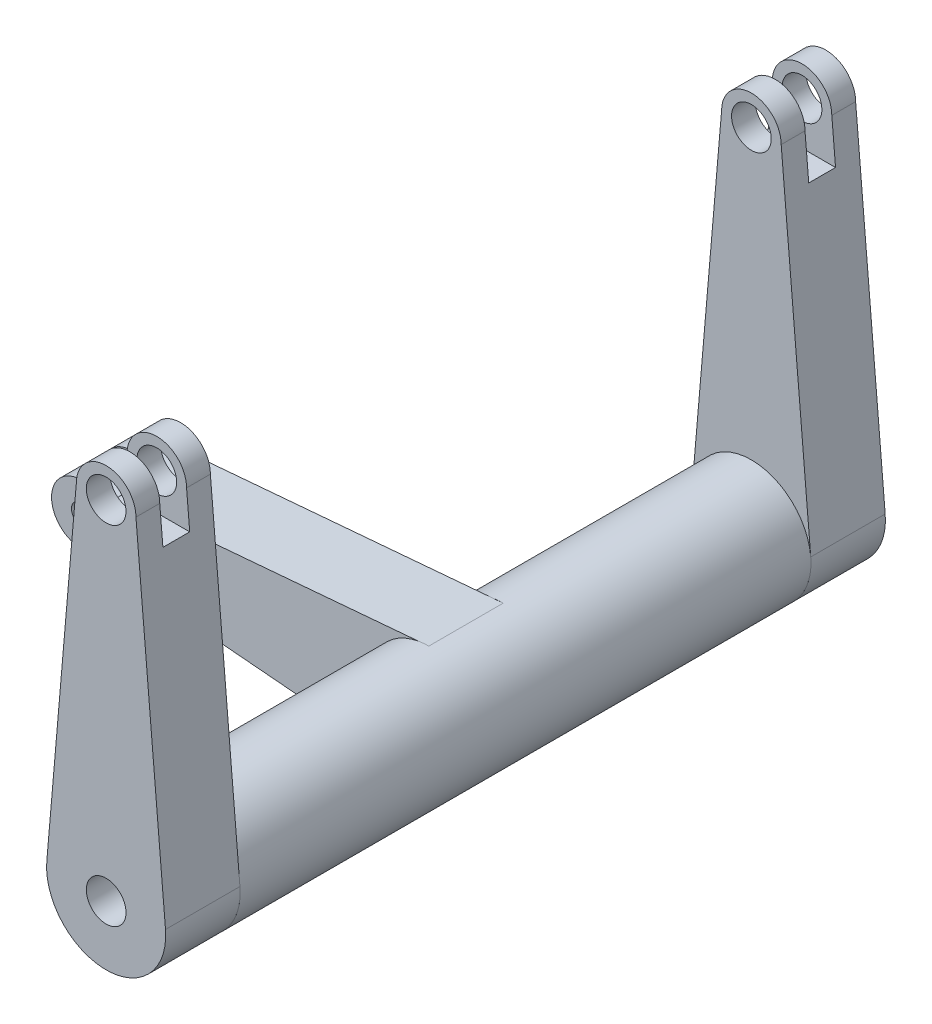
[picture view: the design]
ISO-10303-21;
HEADER;
FILE_DESCRIPTION(('STEP AP214'),'2;1');
FILE_NAME('part.step','',(''),(''),'','','');
FILE_SCHEMA(('AUTOMOTIVE_DESIGN { 1 0 10303 214 1 1 1 1 }'));
ENDSEC;
DATA;
#1=APPLICATION_CONTEXT('core data for automotive mechanical design processes');
#2=APPLICATION_PROTOCOL_DEFINITION('international standard','automotive_design',2000,#1);
#3=PRODUCT_CONTEXT('',#1,'mechanical');
#4=PRODUCT('Part','Part','',(#3));
#5=PRODUCT_RELATED_PRODUCT_CATEGORY('part','',(#4));
#6=PRODUCT_DEFINITION_FORMATION('','',#4);
#7=PRODUCT_DEFINITION_CONTEXT('part definition',#1,'design');
#8=PRODUCT_DEFINITION('design','',#6,#7);
#9=PRODUCT_DEFINITION_SHAPE('','',#8);
#10=(LENGTH_UNIT() NAMED_UNIT(*) SI_UNIT(.MILLI.,.METRE.));
#11=(NAMED_UNIT(*) PLANE_ANGLE_UNIT() SI_UNIT($,.RADIAN.));
#12=(NAMED_UNIT(*) SI_UNIT($,.STERADIAN.) SOLID_ANGLE_UNIT());
#13=UNCERTAINTY_MEASURE_WITH_UNIT(LENGTH_MEASURE(1.E-05),#10,'distance_accuracy_value','');
#14=(GEOMETRIC_REPRESENTATION_CONTEXT(3) GLOBAL_UNCERTAINTY_ASSIGNED_CONTEXT((#13)) GLOBAL_UNIT_ASSIGNED_CONTEXT((#10,
#11,#12)) REPRESENTATION_CONTEXT('',''));
#15=CARTESIAN_POINT('',(0.,0.,0.));
#16=DIRECTION('',(0.,0.,1.));
#17=DIRECTION('',(1.,0.,0.));
#18=AXIS2_PLACEMENT_3D('',#15,#16,#17);
#19=CARTESIAN_POINT('',(88.9,-82.0397739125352,-92.075));
#20=DIRECTION('',(0.,0.,1.));
#21=DIRECTION('',(1.,0.,0.));
#22=AXIS2_PLACEMENT_3D('',#19,#20,#21);
#23=CYLINDRICAL_SURFACE('',#22,7.62);
#24=CARTESIAN_POINT('',(88.9,-82.0397739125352,-79.121));
#25=DIRECTION('',(0.,0.,-1.));
#26=DIRECTION('',(0.,1.,0.));
#27=AXIS2_PLACEMENT_3D('',#24,#25,#26);
#28=CIRCLE('',#27,7.62);
#29=CARTESIAN_POINT('',(81.28,-82.0397739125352,-79.121));
#30=VERTEX_POINT('',#29);
#31=CARTESIAN_POINT('',(96.52,-82.0397739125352,-79.121));
#32=VERTEX_POINT('',#31);
#33=EDGE_CURVE('E245',#30,#32,#28,.T.);
#34=ORIENTED_EDGE('',*,*,#33,.F.);
#35=DIRECTION('',(0.,0.,1.));
#36=VECTOR('',#35,1.);
#37=CARTESIAN_POINT('',(81.28,-82.0397739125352,-92.075));
#38=LINE('',#37,#36);
#39=CARTESIAN_POINT('',(81.28,-82.0397739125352,-73.025));
#40=VERTEX_POINT('',#39);
#41=EDGE_CURVE('E297',#30,#40,#38,.T.);
#42=ORIENTED_EDGE('',*,*,#41,.T.);
#43=CARTESIAN_POINT('',(88.9,-82.0397739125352,-73.025));
#44=DIRECTION('',(0.,0.,-1.));
#45=DIRECTION('',(-1.,0.,0.));
#46=AXIS2_PLACEMENT_3D('',#43,#44,#45);
#47=CIRCLE('',#46,7.62);
#48=CARTESIAN_POINT('',(96.52,-82.0397739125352,-73.025));
#49=VERTEX_POINT('',#48);
#50=EDGE_CURVE('E286',#40,#49,#47,.T.);
#51=ORIENTED_EDGE('',*,*,#50,.T.);
#52=DIRECTION('',(0.,0.,1.));
#53=VECTOR('',#52,1.);
#54=CARTESIAN_POINT('',(96.52,-82.0397739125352,-92.075));
#55=LINE('',#54,#53);
#56=EDGE_CURVE('E319',#32,#49,#55,.T.);
#57=ORIENTED_EDGE('',*,*,#56,.F.);
#58=EDGE_LOOP('',(#34,#42,#51,#57));
#59=FACE_BOUND('',#58,.T.);
#60=ADVANCED_FACE('F32',(#59),#23,.T.);
#61=CARTESIAN_POINT('',(88.9,-82.0397739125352,-85.979));
#62=DIRECTION('',(0.,0.,1.));
#63=DIRECTION('',(0.,-1.,0.));
#64=AXIS2_PLACEMENT_3D('',#61,#62,#63);
#65=CIRCLE('',#64,7.62);
#66=CARTESIAN_POINT('',(96.52,-82.0397739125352,-85.979));
#67=VERTEX_POINT('',#66);
#68=CARTESIAN_POINT('',(81.28,-82.0397739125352,-85.979));
#69=VERTEX_POINT('',#68);
#70=EDGE_CURVE('E47',#67,#69,#65,.T.);
#71=ORIENTED_EDGE('',*,*,#70,.F.);
#72=CARTESIAN_POINT('',(96.52,-82.0397739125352,-92.075));
#73=VERTEX_POINT('',#72);
#74=EDGE_CURVE('E236',#73,#67,#55,.T.);
#75=ORIENTED_EDGE('',*,*,#74,.F.);
#76=CARTESIAN_POINT('',(88.9,-82.0397739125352,-92.075));
#77=DIRECTION('',(0.,0.,-1.));
#78=DIRECTION('',(-1.,0.,0.));
#79=AXIS2_PLACEMENT_3D('',#76,#77,#78);
#80=CIRCLE('',#79,7.62);
#81=CARTESIAN_POINT('',(81.28,-82.0397739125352,-92.075));
#82=VERTEX_POINT('',#81);
#83=EDGE_CURVE('E287',#82,#73,#80,.T.);
#84=ORIENTED_EDGE('',*,*,#83,.F.);
#85=EDGE_CURVE('E310',#82,#69,#38,.T.);
#86=ORIENTED_EDGE('',*,*,#85,.T.);
#87=EDGE_LOOP('',(#71,#75,#84,#86));
#88=FACE_BOUND('',#87,.T.);
#89=ADVANCED_FACE('F595',(#88),#23,.T.);
#90=CARTESIAN_POINT('',(96.52,-82.0397739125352,-92.075));
#91=DIRECTION('',(-0.996292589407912,-0.0860295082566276,0.));
#92=DIRECTION('',(0.0860295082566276,-0.996292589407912,0.));
#93=AXIS2_PLACEMENT_3D('',#90,#91,#92);
#94=PLANE('',#93);
#95=DIRECTION('',(0.0860295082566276,-0.996292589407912,0.));
#96=VECTOR('',#95,1.);
#97=CARTESIAN_POINT('',(96.52,-82.0397739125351,-79.121));
#98=LINE('',#97,#96);
#99=CARTESIAN_POINT('',(97.4756411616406,-93.106885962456,-79.121));
#100=VERTEX_POINT('',#99);
#101=EDGE_CURVE('E227',#32,#100,#98,.T.);
#102=ORIENTED_EDGE('',*,*,#101,.F.);
#103=ORIENTED_EDGE('',*,*,#56,.T.);
#104=DIRECTION('',(0.0860295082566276,-0.996292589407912,0.));
#105=VECTOR('',#104,1.);
#106=CARTESIAN_POINT('',(96.52,-82.0397739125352,-73.025));
#107=LINE('',#106,#105);
#108=CARTESIAN_POINT('',(104.076113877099,-169.545798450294,-73.025));
#109=VERTEX_POINT('',#108);
#110=EDGE_CURVE('E300',#49,#109,#107,.T.);
#111=ORIENTED_EDGE('',*,*,#110,.T.);
#112=CARTESIAN_POINT('',(104.083272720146,-169.628703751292,-73.025));
#113=VERTEX_POINT('',#112);
#114=EDGE_CURVE('E304',#109,#113,#107,.T.);
#115=ORIENTED_EDGE('',*,*,#114,.T.);
#116=DIRECTION('',(0.,0.,1.));
#117=VECTOR('',#116,1.);
#118=CARTESIAN_POINT('',(104.083272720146,-169.628703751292,-92.075));
#119=LINE('',#118,#117);
#120=CARTESIAN_POINT('',(104.083272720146,-169.628703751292,-92.075));
#121=VERTEX_POINT('',#120);
#122=EDGE_CURVE('E316',#121,#113,#119,.T.);
#123=ORIENTED_EDGE('',*,*,#122,.F.);
#124=DIRECTION('',(0.0860295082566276,-0.996292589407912,0.));
#125=VECTOR('',#124,1.);
#126=CARTESIAN_POINT('',(96.52,-82.0397739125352,-92.075));
#127=LINE('',#126,#125);
#128=EDGE_CURVE('E290',#73,#121,#127,.T.);
#129=ORIENTED_EDGE('',*,*,#128,.F.);
#130=ORIENTED_EDGE('',*,*,#74,.T.);
#131=DIRECTION('',(-0.0860295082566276,0.996292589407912,0.));
#132=VECTOR('',#131,1.);
#133=CARTESIAN_POINT('',(96.52,-82.0397739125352,-85.979));
#134=LINE('',#133,#132);
#135=CARTESIAN_POINT('',(97.4756411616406,-93.106885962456,-85.979));
#136=VERTEX_POINT('',#135);
#137=EDGE_CURVE('E230',#136,#67,#134,.T.);
#138=ORIENTED_EDGE('',*,*,#137,.F.);
#139=DIRECTION('',(0.,0.,-1.));
#140=VECTOR('',#139,1.);
#141=CARTESIAN_POINT('',(97.4756411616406,-93.106885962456,-92.075));
#142=LINE('',#141,#140);
#143=EDGE_CURVE('E217',#100,#136,#142,.T.);
#144=ORIENTED_EDGE('',*,*,#143,.F.);
#145=EDGE_LOOP('',(#102,#103,#111,#115,#123,#129,#130,#138,#144));
#146=FACE_BOUND('',#145,.T.);
#147=ADVANCED_FACE('F234',(#146),#94,.F.);
#148=CARTESIAN_POINT('',(73.716727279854,-169.628703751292,-92.075));
#149=DIRECTION('',(0.996292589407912,-0.0860295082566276,0.));
#150=DIRECTION('',(0.0860295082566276,0.996292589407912,0.));
#151=AXIS2_PLACEMENT_3D('',#148,#149,#150);
#152=PLANE('',#151);
#153=DIRECTION('',(0.0860295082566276,0.996292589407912,0.));
#154=VECTOR('',#153,1.);
#155=CARTESIAN_POINT('',(73.716727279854,-169.628703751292,-79.1209999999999));
#156=LINE('',#155,#154);
#157=CARTESIAN_POINT('',(80.3243588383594,-93.106885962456,-79.121));
#158=VERTEX_POINT('',#157);
#159=EDGE_CURVE('E240',#158,#30,#156,.T.);
#160=ORIENTED_EDGE('',*,*,#159,.F.);
#161=DIRECTION('',(0.,0.,1.));
#162=VECTOR('',#161,1.);
#163=CARTESIAN_POINT('',(80.3243588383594,-93.106885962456,-92.075));
#164=LINE('',#163,#162);
#165=CARTESIAN_POINT('',(80.3243588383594,-93.106885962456,-85.979));
#166=VERTEX_POINT('',#165);
#167=EDGE_CURVE('E11',#166,#158,#164,.T.);
#168=ORIENTED_EDGE('',*,*,#167,.F.);
#169=DIRECTION('',(-0.0860295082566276,-0.996292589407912,0.));
#170=VECTOR('',#169,1.);
#171=CARTESIAN_POINT('',(73.716727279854,-169.628703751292,-85.9790000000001));
#172=LINE('',#171,#170);
#173=EDGE_CURVE('E231',#69,#166,#172,.T.);
#174=ORIENTED_EDGE('',*,*,#173,.F.);
#175=ORIENTED_EDGE('',*,*,#85,.F.);
#176=DIRECTION('',(0.0860295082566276,0.996292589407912,0.));
#177=VECTOR('',#176,1.);
#178=CARTESIAN_POINT('',(73.716727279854,-169.628703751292,-92.075));
#179=LINE('',#178,#177);
#180=CARTESIAN_POINT('',(73.716727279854,-169.628703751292,-92.075));
#181=VERTEX_POINT('',#180);
#182=EDGE_CURVE('E295',#181,#82,#179,.T.);
#183=ORIENTED_EDGE('',*,*,#182,.F.);
#184=DIRECTION('',(0.,0.,1.));
#185=VECTOR('',#184,1.);
#186=CARTESIAN_POINT('',(73.716727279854,-169.628703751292,-92.075));
#187=LINE('',#186,#185);
#188=CARTESIAN_POINT('',(73.716727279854,-169.628703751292,-73.025));
#189=VERTEX_POINT('',#188);
#190=EDGE_CURVE('E313',#181,#189,#187,.T.);
#191=ORIENTED_EDGE('',*,*,#190,.T.);
#192=DIRECTION('',(0.0860295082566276,0.996292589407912,0.));
#193=VECTOR('',#192,1.);
#194=CARTESIAN_POINT('',(73.716727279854,-169.628703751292,-73.025));
#195=LINE('',#194,#193);
#196=CARTESIAN_POINT('',(73.7238861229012,-169.545798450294,-73.025));
#197=VERTEX_POINT('',#196);
#198=EDGE_CURVE('E291',#189,#197,#195,.T.);
#199=ORIENTED_EDGE('',*,*,#198,.T.);
#200=EDGE_CURVE('E307',#197,#40,#195,.T.);
#201=ORIENTED_EDGE('',*,*,#200,.T.);
#202=ORIENTED_EDGE('',*,*,#41,.F.);
#203=EDGE_LOOP('',(#160,#168,#174,#175,#183,#191,#199,#201,#202));
#204=FACE_BOUND('',#203,.T.);
#205=ADVANCED_FACE('F570',(#204),#152,.F.);
#206=CARTESIAN_POINT('',(88.9,-82.0397739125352,92.075));
#207=DIRECTION('',(0.,0.,-1.));
#208=DIRECTION('',(-1.,0.,0.));
#209=AXIS2_PLACEMENT_3D('',#206,#207,#208);
#210=CYLINDRICAL_SURFACE('',#209,5.08000000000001);
#211=CARTESIAN_POINT('',(88.9,-82.0397739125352,-73.025));
#212=DIRECTION('',(0.,0.,-1.));
#213=DIRECTION('',(-1.,0.,0.));
#214=AXIS2_PLACEMENT_3D('',#211,#212,#213);
#215=CIRCLE('',#214,5.08000000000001);
#216=CARTESIAN_POINT('',(83.82,-82.0397739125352,-73.025));
#217=VERTEX_POINT('',#216);
#218=EDGE_CURVE('E278',#217,#217,#215,.T.);
#219=ORIENTED_EDGE('',*,*,#218,.F.);
#220=EDGE_LOOP('',(#219));
#221=FACE_BOUND('',#220,.T.);
#222=CARTESIAN_POINT('',(88.9,-82.0397739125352,-79.121));
#223=DIRECTION('',(0.,0.,-1.));
#224=DIRECTION('',(0.,1.,0.));
#225=AXIS2_PLACEMENT_3D('',#222,#223,#224);
#226=CIRCLE('',#225,5.08000000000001);
#227=CARTESIAN_POINT('',(88.9,-76.9597739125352,-79.121));
#228=VERTEX_POINT('',#227);
#229=EDGE_CURVE('E237',#228,#228,#226,.F.);
#230=ORIENTED_EDGE('',*,*,#229,.F.);
#231=EDGE_LOOP('',(#230));
#232=FACE_BOUND('',#231,.T.);
#233=ADVANCED_FACE('F850',(#221,#232),#210,.F.);
#234=CARTESIAN_POINT('',(88.9,-82.0397739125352,-92.075));
#235=DIRECTION('',(0.,0.,-1.));
#236=DIRECTION('',(-1.,0.,0.));
#237=AXIS2_PLACEMENT_3D('',#234,#235,#236);
#238=CIRCLE('',#237,5.08000000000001);
#239=CARTESIAN_POINT('',(83.82,-82.0397739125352,-92.075));
#240=VERTEX_POINT('',#239);
#241=EDGE_CURVE('E272',#240,#240,#238,.T.);
#242=ORIENTED_EDGE('',*,*,#241,.T.);
#243=EDGE_LOOP('',(#242));
#244=FACE_BOUND('',#243,.T.);
#245=CARTESIAN_POINT('',(88.9,-82.0397739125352,-85.979));
#246=DIRECTION('',(0.,0.,1.));
#247=DIRECTION('',(0.,-1.,0.));
#248=AXIS2_PLACEMENT_3D('',#245,#246,#247);
#249=CIRCLE('',#248,5.08000000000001);
#250=CARTESIAN_POINT('',(88.9,-87.1197739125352,-85.979));
#251=VERTEX_POINT('',#250);
#252=EDGE_CURVE('E559',#251,#251,#249,.F.);
#253=ORIENTED_EDGE('',*,*,#252,.F.);
#254=EDGE_LOOP('',(#253));
#255=FACE_BOUND('',#254,.T.);
#256=ADVANCED_FACE('F621',(#244,#255),#210,.F.);
#257=CARTESIAN_POINT('',(88.9,-82.0397739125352,92.075));
#258=DIRECTION('',(0.,0.,-1.));
#259=DIRECTION('',(-1.,0.,0.));
#260=AXIS2_PLACEMENT_3D('',#257,#258,#259);
#261=CYLINDRICAL_SURFACE('',#260,7.62);
#262=CARTESIAN_POINT('',(88.9,-82.0397739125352,85.979));
#263=DIRECTION('',(0.,0.,-1.));
#264=DIRECTION('',(0.,1.,0.));
#265=AXIS2_PLACEMENT_3D('',#262,#263,#264);
#266=CIRCLE('',#265,7.62);
#267=CARTESIAN_POINT('',(81.28,-82.0397739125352,85.979));
#268=VERTEX_POINT('',#267);
#269=CARTESIAN_POINT('',(96.52,-82.0397739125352,85.979));
#270=VERTEX_POINT('',#269);
#271=EDGE_CURVE('E262',#268,#270,#266,.T.);
#272=ORIENTED_EDGE('',*,*,#271,.F.);
#273=DIRECTION('',(0.,0.,-1.));
#274=VECTOR('',#273,1.);
#275=CARTESIAN_POINT('',(81.28,-82.0397739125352,92.075));
#276=LINE('',#275,#274);
#277=CARTESIAN_POINT('',(81.28,-82.0397739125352,92.075));
#278=VERTEX_POINT('',#277);
#279=EDGE_CURVE('E355',#278,#268,#276,.T.);
#280=ORIENTED_EDGE('',*,*,#279,.F.);
#281=CARTESIAN_POINT('',(88.9,-82.0397739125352,92.075));
#282=DIRECTION('',(0.,0.,1.));
#283=DIRECTION('',(1.,0.,0.));
#284=AXIS2_PLACEMENT_3D('',#281,#282,#283);
#285=CIRCLE('',#284,7.62);
#286=CARTESIAN_POINT('',(96.52,-82.0397739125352,92.075));
#287=VERTEX_POINT('',#286);
#288=EDGE_CURVE('E322',#287,#278,#285,.T.);
#289=ORIENTED_EDGE('',*,*,#288,.F.);
#290=DIRECTION('',(0.,0.,-1.));
#291=VECTOR('',#290,1.);
#292=CARTESIAN_POINT('',(96.52,-82.0397739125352,92.075));
#293=LINE('',#292,#291);
#294=EDGE_CURVE('E345',#287,#270,#293,.T.);
#295=ORIENTED_EDGE('',*,*,#294,.T.);
#296=EDGE_LOOP('',(#272,#280,#289,#295));
#297=FACE_BOUND('',#296,.T.);
#298=ADVANCED_FACE('F549',(#297),#261,.T.);
#299=CARTESIAN_POINT('',(88.9,-82.0397739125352,79.121));
#300=DIRECTION('',(0.,0.,1.));
#301=DIRECTION('',(0.,-1.,0.));
#302=AXIS2_PLACEMENT_3D('',#299,#300,#301);
#303=CIRCLE('',#302,7.62);
#304=CARTESIAN_POINT('',(96.52,-82.0397739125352,79.121));
#305=VERTEX_POINT('',#304);
#306=CARTESIAN_POINT('',(81.28,-82.0397739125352,79.121));
#307=VERTEX_POINT('',#306);
#308=EDGE_CURVE('E255',#305,#307,#303,.T.);
#309=ORIENTED_EDGE('',*,*,#308,.F.);
#310=CARTESIAN_POINT('',(96.52,-82.0397739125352,73.025));
#311=VERTEX_POINT('',#310);
#312=EDGE_CURVE('E332',#305,#311,#293,.T.);
#313=ORIENTED_EDGE('',*,*,#312,.T.);
#314=CARTESIAN_POINT('',(88.9,-82.0397739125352,73.025));
#315=DIRECTION('',(0.,0.,1.));
#316=DIRECTION('',(1.,0.,0.));
#317=AXIS2_PLACEMENT_3D('',#314,#315,#316);
#318=CIRCLE('',#317,7.62);
#319=CARTESIAN_POINT('',(81.28,-82.0397739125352,73.025));
#320=VERTEX_POINT('',#319);
#321=EDGE_CURVE('E321',#311,#320,#318,.T.);
#322=ORIENTED_EDGE('',*,*,#321,.T.);
#323=EDGE_CURVE('E354',#307,#320,#276,.T.);
#324=ORIENTED_EDGE('',*,*,#323,.F.);
#325=EDGE_LOOP('',(#309,#313,#322,#324));
#326=FACE_BOUND('',#325,.T.);
#327=ADVANCED_FACE('F530',(#326),#261,.T.);
#328=CARTESIAN_POINT('',(81.28,-82.0397739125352,92.075));
#329=DIRECTION('',(0.996292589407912,-0.0860295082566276,0.));
#330=DIRECTION('',(0.0860295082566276,0.996292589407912,0.));
#331=AXIS2_PLACEMENT_3D('',#328,#329,#330);
#332=PLANE('',#331);
#333=DIRECTION('',(0.0860295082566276,0.996292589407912,0.));
#334=VECTOR('',#333,1.);
#335=CARTESIAN_POINT('',(81.28,-82.0397739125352,85.979));
#336=LINE('',#335,#334);
#337=CARTESIAN_POINT('',(80.4738172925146,-91.3760339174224,85.979));
#338=VERTEX_POINT('',#337);
#339=EDGE_CURVE('E264',#338,#268,#336,.T.);
#340=ORIENTED_EDGE('',*,*,#339,.F.);
#341=DIRECTION('',(0.,0.,1.));
#342=VECTOR('',#341,1.);
#343=CARTESIAN_POINT('',(80.4738172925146,-91.3760339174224,92.075));
#344=LINE('',#343,#342);
#345=CARTESIAN_POINT('',(80.4738172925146,-91.3760339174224,79.121));
#346=VERTEX_POINT('',#345);
#347=EDGE_CURVE('E266',#346,#338,#344,.T.);
#348=ORIENTED_EDGE('',*,*,#347,.F.);
#349=DIRECTION('',(-0.0860295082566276,-0.996292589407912,0.));
#350=VECTOR('',#349,1.);
#351=CARTESIAN_POINT('',(81.28,-82.0397739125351,79.121));
#352=LINE('',#351,#350);
#353=EDGE_CURVE('E257',#307,#346,#352,.T.);
#354=ORIENTED_EDGE('',*,*,#353,.F.);
#355=ORIENTED_EDGE('',*,*,#323,.T.);
#356=DIRECTION('',(-0.0860295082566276,-0.996292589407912,0.));
#357=VECTOR('',#356,1.);
#358=CARTESIAN_POINT('',(81.28,-82.0397739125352,73.025));
#359=LINE('',#358,#357);
#360=CARTESIAN_POINT('',(73.7238861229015,-169.545798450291,73.025));
#361=VERTEX_POINT('',#360);
#362=EDGE_CURVE('E335',#320,#361,#359,.T.);
#363=ORIENTED_EDGE('',*,*,#362,.T.);
#364=CARTESIAN_POINT('',(73.716727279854,-169.628703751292,73.025));
#365=VERTEX_POINT('',#364);
#366=EDGE_CURVE('E339',#361,#365,#359,.T.);
#367=ORIENTED_EDGE('',*,*,#366,.T.);
#368=DIRECTION('',(0.,0.,-1.));
#369=VECTOR('',#368,1.);
#370=CARTESIAN_POINT('',(73.716727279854,-169.628703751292,92.075));
#371=LINE('',#370,#369);
#372=CARTESIAN_POINT('',(73.716727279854,-169.628703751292,92.075));
#373=VERTEX_POINT('',#372);
#374=EDGE_CURVE('E351',#373,#365,#371,.T.);
#375=ORIENTED_EDGE('',*,*,#374,.F.);
#376=DIRECTION('',(-0.0860295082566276,-0.996292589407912,0.));
#377=VECTOR('',#376,1.);
#378=CARTESIAN_POINT('',(81.28,-82.0397739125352,92.075));
#379=LINE('',#378,#377);
#380=EDGE_CURVE('E325',#278,#373,#379,.T.);
#381=ORIENTED_EDGE('',*,*,#380,.F.);
#382=ORIENTED_EDGE('',*,*,#279,.T.);
#383=EDGE_LOOP('',(#340,#348,#354,#355,#363,#367,#375,#381,#382));
#384=FACE_BOUND('',#383,.T.);
#385=ADVANCED_FACE('F523',(#384),#332,.F.);
#386=CARTESIAN_POINT('',(104.083272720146,-169.628703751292,92.075));
#387=DIRECTION('',(-0.996292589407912,-0.0860295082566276,0.));
#388=DIRECTION('',(0.0860295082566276,-0.996292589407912,0.));
#389=AXIS2_PLACEMENT_3D('',#386,#387,#388);
#390=PLANE('',#389);
#391=DIRECTION('',(0.0860295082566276,-0.996292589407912,0.));
#392=VECTOR('',#391,1.);
#393=CARTESIAN_POINT('',(104.083272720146,-169.628703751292,85.979));
#394=LINE('',#393,#392);
#395=CARTESIAN_POINT('',(97.3261827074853,-91.3760339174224,85.979));
#396=VERTEX_POINT('',#395);
#397=EDGE_CURVE('E260',#270,#396,#394,.T.);
#398=ORIENTED_EDGE('',*,*,#397,.F.);
#399=ORIENTED_EDGE('',*,*,#294,.F.);
#400=DIRECTION('',(-0.0860295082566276,0.996292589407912,0.));
#401=VECTOR('',#400,1.);
#402=CARTESIAN_POINT('',(104.083272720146,-169.628703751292,92.075));
#403=LINE('',#402,#401);
#404=CARTESIAN_POINT('',(104.083272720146,-169.628703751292,92.075));
#405=VERTEX_POINT('',#404);
#406=EDGE_CURVE('E330',#405,#287,#403,.T.);
#407=ORIENTED_EDGE('',*,*,#406,.F.);
#408=DIRECTION('',(0.,0.,-1.));
#409=VECTOR('',#408,1.);
#410=CARTESIAN_POINT('',(104.083272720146,-169.628703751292,92.075));
#411=LINE('',#410,#409);
#412=CARTESIAN_POINT('',(104.083272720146,-169.628703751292,73.025));
#413=VERTEX_POINT('',#412);
#414=EDGE_CURVE('E348',#405,#413,#411,.T.);
#415=ORIENTED_EDGE('',*,*,#414,.T.);
#416=DIRECTION('',(-0.0860295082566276,0.996292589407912,0.));
#417=VECTOR('',#416,1.);
#418=CARTESIAN_POINT('',(104.083272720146,-169.628703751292,73.025));
#419=LINE('',#418,#417);
#420=CARTESIAN_POINT('',(104.076113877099,-169.545798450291,73.025));
#421=VERTEX_POINT('',#420);
#422=EDGE_CURVE('E326',#413,#421,#419,.T.);
#423=ORIENTED_EDGE('',*,*,#422,.T.);
#424=EDGE_CURVE('E342',#421,#311,#419,.T.);
#425=ORIENTED_EDGE('',*,*,#424,.T.);
#426=ORIENTED_EDGE('',*,*,#312,.F.);
#427=DIRECTION('',(-0.0860295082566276,0.996292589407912,0.));
#428=VECTOR('',#427,1.);
#429=CARTESIAN_POINT('',(104.083272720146,-169.628703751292,79.1209999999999));
#430=LINE('',#429,#428);
#431=CARTESIAN_POINT('',(97.3261827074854,-91.3760339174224,79.121));
#432=VERTEX_POINT('',#431);
#433=EDGE_CURVE('E253',#432,#305,#430,.T.);
#434=ORIENTED_EDGE('',*,*,#433,.F.);
#435=DIRECTION('',(0.,0.,-1.));
#436=VECTOR('',#435,1.);
#437=CARTESIAN_POINT('',(97.3261827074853,-91.3760339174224,92.075));
#438=LINE('',#437,#436);
#439=EDGE_CURVE('E40',#396,#432,#438,.T.);
#440=ORIENTED_EDGE('',*,*,#439,.F.);
#441=EDGE_LOOP('',(#398,#399,#407,#415,#423,#425,#426,#434,#440));
#442=FACE_BOUND('',#441,.T.);
#443=ADVANCED_FACE('F535',(#442),#390,.F.);
#444=CARTESIAN_POINT('',(88.9,-82.0397739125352,92.075));
#445=DIRECTION('',(0.,0.,-1.));
#446=DIRECTION('',(-1.,0.,0.));
#447=AXIS2_PLACEMENT_3D('',#444,#445,#446);
#448=CIRCLE('',#447,5.08000000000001);
#449=CARTESIAN_POINT('',(83.82,-82.0397739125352,92.075));
#450=VERTEX_POINT('',#449);
#451=EDGE_CURVE('E275',#450,#450,#448,.T.);
#452=ORIENTED_EDGE('',*,*,#451,.F.);
#453=EDGE_LOOP('',(#452));
#454=FACE_BOUND('',#453,.T.);
#455=CARTESIAN_POINT('',(88.9,-82.0397739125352,85.979));
#456=DIRECTION('',(0.,0.,-1.));
#457=DIRECTION('',(0.,1.,0.));
#458=AXIS2_PLACEMENT_3D('',#455,#456,#457);
#459=CIRCLE('',#458,5.08000000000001);
#460=CARTESIAN_POINT('',(88.9,-76.9597739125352,85.979));
#461=VERTEX_POINT('',#460);
#462=EDGE_CURVE('E259',#461,#461,#459,.F.);
#463=ORIENTED_EDGE('',*,*,#462,.F.);
#464=EDGE_LOOP('',(#463));
#465=FACE_BOUND('',#464,.T.);
#466=ADVANCED_FACE('F614',(#454,#465),#210,.F.);
#467=CARTESIAN_POINT('',(88.9,-82.0397739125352,73.025));
#468=DIRECTION('',(0.,0.,1.));
#469=DIRECTION('',(1.,0.,0.));
#470=AXIS2_PLACEMENT_3D('',#467,#468,#469);
#471=CIRCLE('',#470,5.08000000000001);
#472=CARTESIAN_POINT('',(93.98,-82.0397739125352,73.025));
#473=VERTEX_POINT('',#472);
#474=EDGE_CURVE('E283',#473,#473,#471,.T.);
#475=ORIENTED_EDGE('',*,*,#474,.F.);
#476=EDGE_LOOP('',(#475));
#477=FACE_BOUND('',#476,.T.);
#478=CARTESIAN_POINT('',(88.9,-82.0397739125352,79.121));
#479=DIRECTION('',(0.,0.,1.));
#480=DIRECTION('',(0.,-1.,0.));
#481=AXIS2_PLACEMENT_3D('',#478,#479,#480);
#482=CIRCLE('',#481,5.08000000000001);
#483=CARTESIAN_POINT('',(88.9,-87.1197739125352,79.121));
#484=VERTEX_POINT('',#483);
#485=EDGE_CURVE('E252',#484,#484,#482,.F.);
#486=ORIENTED_EDGE('',*,*,#485,.F.);
#487=EDGE_LOOP('',(#486));
#488=FACE_BOUND('',#487,.T.);
#489=ADVANCED_FACE('F652',(#477,#488),#210,.F.);
#490=CARTESIAN_POINT('',(88.9,-170.939773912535,-9.525));
#491=DIRECTION('',(0.,0.,1.));
#492=DIRECTION('',(1.,0.,0.));
#493=AXIS2_PLACEMENT_3D('',#490,#491,#492);
#494=PLANE('',#493);
#495=CARTESIAN_POINT('',(0.,-170.939773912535,-9.525));
#496=DIRECTION('',(0.,0.,1.));
#497=DIRECTION('',(1.,0.,0.));
#498=AXIS2_PLACEMENT_3D('',#495,#496,#497);
#499=CIRCLE('',#498,2.54);
#500=CARTESIAN_POINT('',(-2.54,-170.939773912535,-9.525));
#501=VERTEX_POINT('',#500);
#502=EDGE_CURVE('E442',#501,#501,#499,.T.);
#503=ORIENTED_EDGE('',*,*,#502,.T.);
#504=EDGE_LOOP('',(#503));
#505=FACE_BOUND('',#504,.T.);
#506=CARTESIAN_POINT('',(88.9,-170.939773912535,-9.525));
#507=DIRECTION('',(0.,0.,-1.));
#508=DIRECTION('',(-1.,0.,0.));
#509=AXIS2_PLACEMENT_3D('',#506,#507,#508);
#510=CIRCLE('',#509,15.24);
#511=CARTESIAN_POINT('',(86.3064829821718,-185.957472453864,-9.525));
#512=VERTEX_POINT('',#511);
#513=CARTESIAN_POINT('',(86.3064829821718,-155.922075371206,-9.525));
#514=VERTEX_POINT('',#513);
#515=EDGE_CURVE('E369',#512,#514,#510,.T.);
#516=ORIENTED_EDGE('',*,*,#515,.F.);
#517=DIRECTION('',(0.996346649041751,-0.085401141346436,0.));
#518=VECTOR('',#517,1.);
#519=CARTESIAN_POINT('',(0.,-178.559773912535,-9.525));
#520=LINE('',#519,#518);
#521=CARTESIAN_POINT('',(0.,-178.559773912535,-9.525));
#522=VERTEX_POINT('',#521);
#523=EDGE_CURVE('E381',#522,#512,#520,.T.);
#524=ORIENTED_EDGE('',*,*,#523,.F.);
#525=CARTESIAN_POINT('',(0.,-170.939773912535,-9.525));
#526=DIRECTION('',(0.,0.,1.));
#527=DIRECTION('',(1.,0.,0.));
#528=AXIS2_PLACEMENT_3D('',#525,#526,#527);
#529=CIRCLE('',#528,7.61999999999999);
#530=CARTESIAN_POINT('',(0.,-163.319773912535,-9.525));
#531=VERTEX_POINT('',#530);
#532=EDGE_CURVE('E382',#531,#522,#529,.T.);
#533=ORIENTED_EDGE('',*,*,#532,.F.);
#534=DIRECTION('',(-0.996346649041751,-0.085401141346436,0.));
#535=VECTOR('',#534,1.);
#536=CARTESIAN_POINT('',(0.,-163.319773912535,-9.525));
#537=LINE('',#536,#535);
#538=EDGE_CURVE('E446',#514,#531,#537,.T.);
#539=ORIENTED_EDGE('',*,*,#538,.F.);
#540=EDGE_LOOP('',(#516,#524,#533,#539));
#541=FACE_BOUND('',#540,.T.);
#542=ADVANCED_FACE('F478',(#505,#541),#494,.F.);
#543=CARTESIAN_POINT('',(0.,-163.319773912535,9.525));
#544=DIRECTION('',(0.085401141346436,-0.996346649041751,0.));
#545=DIRECTION('',(0.996346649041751,0.085401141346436,0.));
#546=AXIS2_PLACEMENT_3D('',#543,#544,#545);
#547=PLANE('',#546);
#548=DIRECTION('',(-0.996346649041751,-0.085401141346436,0.));
#549=VECTOR('',#548,1.);
#550=CARTESIAN_POINT('',(0.,-163.319773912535,-3.429));
#551=LINE('',#550,#549);
#552=CARTESIAN_POINT('',(6.35,-162.775488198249,-3.429));
#553=VERTEX_POINT('',#552);
#554=CARTESIAN_POINT('',(0.,-163.319773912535,-3.429));
#555=VERTEX_POINT('',#554);
#556=EDGE_CURVE('E437',#553,#555,#551,.T.);
#557=ORIENTED_EDGE('',*,*,#556,.F.);
#558=DIRECTION('',(0.,0.,1.));
#559=VECTOR('',#558,1.);
#560=CARTESIAN_POINT('',(6.35,-162.775488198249,9.525));
#561=LINE('',#560,#559);
#562=CARTESIAN_POINT('',(6.35,-162.775488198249,3.429));
#563=VERTEX_POINT('',#562);
#564=EDGE_CURVE('E439',#553,#563,#561,.T.);
#565=ORIENTED_EDGE('',*,*,#564,.T.);
#566=DIRECTION('',(0.996346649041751,0.085401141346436,0.));
#567=VECTOR('',#566,1.);
#568=CARTESIAN_POINT('',(0.,-163.319773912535,3.429));
#569=LINE('',#568,#567);
#570=CARTESIAN_POINT('',(0.,-163.319773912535,3.429));
#571=VERTEX_POINT('',#570);
#572=EDGE_CURVE('E409',#571,#563,#569,.T.);
#573=ORIENTED_EDGE('',*,*,#572,.F.);
#574=DIRECTION('',(0.,0.,-1.));
#575=VECTOR('',#574,1.);
#576=CARTESIAN_POINT('',(0.,-163.319773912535,9.525));
#577=LINE('',#576,#575);
#578=CARTESIAN_POINT('',(0.,-163.319773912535,9.525));
#579=VERTEX_POINT('',#578);
#580=EDGE_CURVE('E396',#579,#571,#577,.T.);
#581=ORIENTED_EDGE('',*,*,#580,.F.);
#582=DIRECTION('',(-0.996346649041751,-0.085401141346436,0.));
#583=VECTOR('',#582,1.);
#584=CARTESIAN_POINT('',(0.,-163.319773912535,9.525));
#585=LINE('',#584,#583);
#586=CARTESIAN_POINT('',(86.3064829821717,-155.922075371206,9.525));
#587=VERTEX_POINT('',#586);
#588=EDGE_CURVE('E390',#587,#579,#585,.T.);
#589=ORIENTED_EDGE('',*,*,#588,.F.);
#590=CARTESIAN_POINT('',(88.9,-155.699773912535,9.525));
#591=VERTEX_POINT('',#590);
#592=EDGE_CURVE('E451',#591,#587,#585,.T.);
#593=ORIENTED_EDGE('',*,*,#592,.F.);
#594=DIRECTION('',(0.,0.,-1.));
#595=VECTOR('',#594,1.);
#596=CARTESIAN_POINT('',(88.9,-155.699773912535,9.525));
#597=LINE('',#596,#595);
#598=CARTESIAN_POINT('',(88.9,-155.699773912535,-9.525));
#599=VERTEX_POINT('',#598);
#600=EDGE_CURVE('E399',#591,#599,#597,.T.);
#601=ORIENTED_EDGE('',*,*,#600,.T.);
#602=EDGE_CURVE('E383',#599,#514,#537,.T.);
#603=ORIENTED_EDGE('',*,*,#602,.T.);
#604=ORIENTED_EDGE('',*,*,#538,.T.);
#605=EDGE_CURVE('E394',#555,#531,#577,.T.);
#606=ORIENTED_EDGE('',*,*,#605,.F.);
#607=EDGE_LOOP('',(#557,#565,#573,#581,#589,#593,#601,#603,#604,#606));
#608=FACE_BOUND('',#607,.T.);
#609=ADVANCED_FACE('F504',(#608),#547,.F.);
#610=CARTESIAN_POINT('',(0.,-170.939773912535,9.525));
#611=DIRECTION('',(0.,0.,-1.));
#612=DIRECTION('',(-1.,0.,0.));
#613=AXIS2_PLACEMENT_3D('',#610,#611,#612);
#614=CYLINDRICAL_SURFACE('',#613,7.61999999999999);
#615=CARTESIAN_POINT('',(0.,-170.939773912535,-3.429));
#616=DIRECTION('',(0.,0.,1.));
#617=DIRECTION('',(0.,-1.,0.));
#618=AXIS2_PLACEMENT_3D('',#615,#616,#617);
#619=CIRCLE('',#618,7.61999999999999);
#620=CARTESIAN_POINT('',(0.,-178.559773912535,-3.429));
#621=VERTEX_POINT('',#620);
#622=EDGE_CURVE('E435',#555,#621,#619,.T.);
#623=ORIENTED_EDGE('',*,*,#622,.F.);
#624=ORIENTED_EDGE('',*,*,#605,.T.);
#625=ORIENTED_EDGE('',*,*,#532,.T.);
#626=DIRECTION('',(0.,0.,-1.));
#627=VECTOR('',#626,1.);
#628=CARTESIAN_POINT('',(0.,-178.559773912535,9.525));
#629=LINE('',#628,#627);
#630=EDGE_CURVE('E395',#621,#522,#629,.T.);
#631=ORIENTED_EDGE('',*,*,#630,.F.);
#632=EDGE_LOOP('',(#623,#624,#625,#631));
#633=FACE_BOUND('',#632,.T.);
#634=ADVANCED_FACE('F476',(#633),#614,.T.);
#635=CARTESIAN_POINT('',(0.,-170.939773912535,3.429));
#636=DIRECTION('',(0.,0.,-1.));
#637=DIRECTION('',(0.,1.,0.));
#638=AXIS2_PLACEMENT_3D('',#635,#636,#637);
#639=CIRCLE('',#638,7.61999999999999);
#640=CARTESIAN_POINT('',(0.,-178.559773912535,3.429));
#641=VERTEX_POINT('',#640);
#642=EDGE_CURVE('E430',#641,#571,#639,.T.);
#643=ORIENTED_EDGE('',*,*,#642,.F.);
#644=CARTESIAN_POINT('',(0.,-178.559773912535,9.525));
#645=VERTEX_POINT('',#644);
#646=EDGE_CURVE('E391',#645,#641,#629,.T.);
#647=ORIENTED_EDGE('',*,*,#646,.F.);
#648=CARTESIAN_POINT('',(0.,-170.939773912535,9.525));
#649=DIRECTION('',(0.,0.,1.));
#650=DIRECTION('',(1.,0.,0.));
#651=AXIS2_PLACEMENT_3D('',#648,#649,#650);
#652=CIRCLE('',#651,7.61999999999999);
#653=EDGE_CURVE('E452',#579,#645,#652,.T.);
#654=ORIENTED_EDGE('',*,*,#653,.F.);
#655=ORIENTED_EDGE('',*,*,#580,.T.);
#656=EDGE_LOOP('',(#643,#647,#654,#655));
#657=FACE_BOUND('',#656,.T.);
#658=ADVANCED_FACE('F656',(#657),#614,.T.);
#659=CARTESIAN_POINT('',(0.,-178.559773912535,9.525));
#660=DIRECTION('',(0.085401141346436,0.996346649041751,0.));
#661=DIRECTION('',(-0.996346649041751,0.085401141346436,0.));
#662=AXIS2_PLACEMENT_3D('',#659,#660,#661);
#663=PLANE('',#662);
#664=DIRECTION('',(0.996346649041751,-0.085401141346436,0.));
#665=VECTOR('',#664,1.);
#666=CARTESIAN_POINT('',(0.,-178.559773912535,-3.429));
#667=LINE('',#666,#665);
#668=CARTESIAN_POINT('',(6.35,-179.104059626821,-3.429));
#669=VERTEX_POINT('',#668);
#670=EDGE_CURVE('E408',#621,#669,#667,.T.);
#671=ORIENTED_EDGE('',*,*,#670,.F.);
#672=ORIENTED_EDGE('',*,*,#630,.T.);
#673=ORIENTED_EDGE('',*,*,#523,.T.);
#674=CARTESIAN_POINT('',(88.9,-186.179773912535,-9.525));
#675=VERTEX_POINT('',#674);
#676=EDGE_CURVE('E377',#512,#675,#520,.T.);
#677=ORIENTED_EDGE('',*,*,#676,.T.);
#678=DIRECTION('',(0.,0.,-1.));
#679=VECTOR('',#678,1.);
#680=CARTESIAN_POINT('',(88.9,-186.179773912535,9.525));
#681=LINE('',#680,#679);
#682=CARTESIAN_POINT('',(88.9,-186.179773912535,9.525));
#683=VERTEX_POINT('',#682);
#684=EDGE_CURVE('E461',#683,#675,#681,.T.);
#685=ORIENTED_EDGE('',*,*,#684,.F.);
#686=DIRECTION('',(0.996346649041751,-0.085401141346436,0.));
#687=VECTOR('',#686,1.);
#688=CARTESIAN_POINT('',(0.,-178.559773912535,9.525));
#689=LINE('',#688,#687);
#690=CARTESIAN_POINT('',(86.3064829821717,-185.957472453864,9.525));
#691=VERTEX_POINT('',#690);
#692=EDGE_CURVE('E458',#691,#683,#689,.T.);
#693=ORIENTED_EDGE('',*,*,#692,.F.);
#694=EDGE_CURVE('E460',#645,#691,#689,.T.);
#695=ORIENTED_EDGE('',*,*,#694,.F.);
#696=ORIENTED_EDGE('',*,*,#646,.T.);
#697=DIRECTION('',(-0.996346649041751,0.085401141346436,0.));
#698=VECTOR('',#697,1.);
#699=CARTESIAN_POINT('',(0.,-178.559773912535,3.429));
#700=LINE('',#699,#698);
#701=CARTESIAN_POINT('',(6.35,-179.104059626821,3.429));
#702=VERTEX_POINT('',#701);
#703=EDGE_CURVE('E403',#702,#641,#700,.T.);
#704=ORIENTED_EDGE('',*,*,#703,.F.);
#705=DIRECTION('',(0.,0.,-1.));
#706=VECTOR('',#705,1.);
#707=CARTESIAN_POINT('',(6.35,-179.104059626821,9.525));
#708=LINE('',#707,#706);
#709=EDGE_CURVE('E410',#702,#669,#708,.T.);
#710=ORIENTED_EDGE('',*,*,#709,.T.);
#711=EDGE_LOOP('',(#671,#672,#673,#677,#685,#693,#695,#696,#704,#710));
#712=FACE_BOUND('',#711,.T.);
#713=ADVANCED_FACE('F482',(#712),#663,.F.);
#714=CARTESIAN_POINT('',(0.,-170.939773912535,9.525));
#715=DIRECTION('',(0.,0.,-1.));
#716=DIRECTION('',(-1.,0.,0.));
#717=AXIS2_PLACEMENT_3D('',#714,#715,#716);
#718=CYLINDRICAL_SURFACE('',#717,2.54);
#719=CARTESIAN_POINT('',(0.,-170.939773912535,-3.429));
#720=DIRECTION('',(0.,0.,1.));
#721=DIRECTION('',(0.,-1.,0.));
#722=AXIS2_PLACEMENT_3D('',#719,#720,#721);
#723=CIRCLE('',#722,2.54);
#724=CARTESIAN_POINT('',(-2.54,-170.939773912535,-3.429));
#725=VERTEX_POINT('',#724);
#726=EDGE_CURVE('E405',#725,#725,#723,.T.);
#727=CARTESIAN_POINT('',(-2.54,-170.939773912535,-9.525));
#728=CARTESIAN_POINT('',(-2.54,-170.939773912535,-9.4615));
#729=CARTESIAN_POINT('',(-2.54,-170.939773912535,-9.398));
#730=CARTESIAN_POINT('',(-2.54,-170.939773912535,-9.271));
#731=CARTESIAN_POINT('',(-2.54,-170.939773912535,-9.2075));
#732=CARTESIAN_POINT('',(-2.54,-170.939773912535,-9.0805));
#733=CARTESIAN_POINT('',(-2.54,-170.939773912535,-9.017));
#734=CARTESIAN_POINT('',(-2.54,-170.939773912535,-8.89));
#735=CARTESIAN_POINT('',(-2.54,-170.939773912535,-8.8265));
#736=CARTESIAN_POINT('',(-2.54,-170.939773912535,-8.6995));
#737=CARTESIAN_POINT('',(-2.54,-170.939773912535,-8.636));
#738=CARTESIAN_POINT('',(-2.54,-170.939773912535,-8.509));
#739=CARTESIAN_POINT('',(-2.54,-170.939773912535,-8.4455));
#740=CARTESIAN_POINT('',(-2.54,-170.939773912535,-8.3185));
#741=CARTESIAN_POINT('',(-2.54,-170.939773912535,-8.255));
#742=CARTESIAN_POINT('',(-2.54,-170.939773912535,-8.128));
#743=CARTESIAN_POINT('',(-2.54,-170.939773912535,-8.0645));
#744=CARTESIAN_POINT('',(-2.54,-170.939773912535,-7.9375));
#745=CARTESIAN_POINT('',(-2.54,-170.939773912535,-7.874));
#746=CARTESIAN_POINT('',(-2.54,-170.939773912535,-7.747));
#747=CARTESIAN_POINT('',(-2.54,-170.939773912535,-7.6835));
#748=CARTESIAN_POINT('',(-2.54,-170.939773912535,-7.5565));
#749=CARTESIAN_POINT('',(-2.54,-170.939773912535,-7.493));
#750=CARTESIAN_POINT('',(-2.54,-170.939773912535,-7.366));
#751=CARTESIAN_POINT('',(-2.54,-170.939773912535,-7.3025));
#752=CARTESIAN_POINT('',(-2.54,-170.939773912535,-7.1755));
#753=CARTESIAN_POINT('',(-2.54,-170.939773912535,-7.112));
#754=CARTESIAN_POINT('',(-2.54,-170.939773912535,-6.985));
#755=CARTESIAN_POINT('',(-2.54,-170.939773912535,-6.9215));
#756=CARTESIAN_POINT('',(-2.54,-170.939773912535,-6.7945));
#757=CARTESIAN_POINT('',(-2.54,-170.939773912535,-6.731));
#758=CARTESIAN_POINT('',(-2.54,-170.939773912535,-6.604));
#759=CARTESIAN_POINT('',(-2.54,-170.939773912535,-6.5405));
#760=CARTESIAN_POINT('',(-2.54,-170.939773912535,-6.4135));
#761=CARTESIAN_POINT('',(-2.54,-170.939773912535,-6.35));
#762=CARTESIAN_POINT('',(-2.54,-170.939773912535,-6.223));
#763=CARTESIAN_POINT('',(-2.54,-170.939773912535,-6.1595));
#764=CARTESIAN_POINT('',(-2.54,-170.939773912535,-6.0325));
#765=CARTESIAN_POINT('',(-2.54,-170.939773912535,-5.969));
#766=CARTESIAN_POINT('',(-2.54,-170.939773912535,-5.842));
#767=CARTESIAN_POINT('',(-2.54,-170.939773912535,-5.7785));
#768=CARTESIAN_POINT('',(-2.54,-170.939773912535,-5.6515));
#769=CARTESIAN_POINT('',(-2.54,-170.939773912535,-5.588));
#770=CARTESIAN_POINT('',(-2.54,-170.939773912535,-5.461));
#771=CARTESIAN_POINT('',(-2.54,-170.939773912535,-5.3975));
#772=CARTESIAN_POINT('',(-2.54,-170.939773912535,-5.2705));
#773=CARTESIAN_POINT('',(-2.54,-170.939773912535,-5.207));
#774=CARTESIAN_POINT('',(-2.54,-170.939773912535,-5.08));
#775=CARTESIAN_POINT('',(-2.54,-170.939773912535,-5.0165));
#776=CARTESIAN_POINT('',(-2.54,-170.939773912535,-4.8895));
#777=CARTESIAN_POINT('',(-2.54,-170.939773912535,-4.826));
#778=CARTESIAN_POINT('',(-2.54,-170.939773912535,-4.699));
#779=CARTESIAN_POINT('',(-2.54,-170.939773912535,-4.6355));
#780=CARTESIAN_POINT('',(-2.54,-170.939773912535,-4.5085));
#781=CARTESIAN_POINT('',(-2.54,-170.939773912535,-4.445));
#782=CARTESIAN_POINT('',(-2.54,-170.939773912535,-4.318));
#783=CARTESIAN_POINT('',(-2.54,-170.939773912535,-4.2545));
#784=CARTESIAN_POINT('',(-2.54,-170.939773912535,-4.1275));
#785=CARTESIAN_POINT('',(-2.54,-170.939773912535,-4.064));
#786=CARTESIAN_POINT('',(-2.54,-170.939773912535,-3.937));
#787=CARTESIAN_POINT('',(-2.54,-170.939773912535,-3.8735));
#788=CARTESIAN_POINT('',(-2.54,-170.939773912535,-3.7465));
#789=CARTESIAN_POINT('',(-2.54,-170.939773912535,-3.683));
#790=CARTESIAN_POINT('',(-2.54,-170.939773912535,-3.556));
#791=CARTESIAN_POINT('',(-2.54,-170.939773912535,-3.4925));
#792=CARTESIAN_POINT('',(-2.54,-170.939773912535,-3.429));
#793=B_SPLINE_CURVE_WITH_KNOTS('',3,(#727,#728,#729,#730,#731,#732,#733,#734,#735,#736,#737,
#738,#739,#740,#741,#742,#743,#744,#745,#746,#747,#748,#749,#750,#751,#752,#753,#754,#755,#756,
#757,#758,#759,#760,#761,#762,#763,#764,#765,#766,#767,#768,#769,#770,#771,#772,#773,#774,#775,
#776,#777,#778,#779,#780,#781,#782,#783,#784,#785,#786,#787,#788,#789,#790,#791,#792),
.UNSPECIFIED.,.F.,.F.,(4,2,2,2,2,2,2,2,2,2,2,2,2,2,2,2,2,2,2,2,2,2,2,2,2,2,2,2,2,2,2,2,4),(0.,
0.1905,0.380999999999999,0.571499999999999,0.761999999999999,0.952499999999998,1.143,1.3335,
1.524,1.7145,1.905,2.0955,2.286,2.4765,2.667,2.8575,3.048,3.2385,3.429,3.6195,3.81,4.0005,4.191,
4.3815,4.572,4.7625,4.953,5.1435,5.334,5.5245,5.715,5.9055,6.096),.UNSPECIFIED.);
#794=EDGE_CURVE('BSEAM643',#501,#725,#793,.T.);
#795=ORIENTED_EDGE('',*,*,#502,.F.);
#796=ORIENTED_EDGE('',*,*,#726,.T.);
#797=ORIENTED_EDGE('',*,*,#794,.T.);
#798=ORIENTED_EDGE('',*,*,#794,.F.);
#799=EDGE_LOOP('',(#795,#797,#796,#798));
#800=FACE_BOUND('',#799,.T.);
#801=ADVANCED_FACE('F643',(#800),#718,.F.);
#802=CARTESIAN_POINT('',(0.,-170.939773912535,9.525));
#803=DIRECTION('',(0.,0.,1.));
#804=DIRECTION('',(1.,0.,0.));
#805=AXIS2_PLACEMENT_3D('',#802,#803,#804);
#806=CIRCLE('',#805,2.54);
#807=CARTESIAN_POINT('',(-2.54,-170.939773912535,9.525));
#808=VERTEX_POINT('',#807);
#809=EDGE_CURVE('E443',#808,#808,#806,.T.);
#810=CARTESIAN_POINT('',(0.,-170.939773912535,3.429));
#811=DIRECTION('',(0.,0.,-1.));
#812=DIRECTION('',(0.,1.,0.));
#813=AXIS2_PLACEMENT_3D('',#810,#811,#812);
#814=CIRCLE('',#813,2.54);
#815=CARTESIAN_POINT('',(-2.54,-170.939773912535,3.429));
#816=VERTEX_POINT('',#815);
#817=EDGE_CURVE('E400',#816,#816,#814,.T.);
#818=CARTESIAN_POINT('',(-2.54,-170.939773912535,9.525));
#819=CARTESIAN_POINT('',(-2.54,-170.939773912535,9.4615));
#820=CARTESIAN_POINT('',(-2.54,-170.939773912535,9.398));
#821=CARTESIAN_POINT('',(-2.54,-170.939773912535,9.271));
#822=CARTESIAN_POINT('',(-2.54,-170.939773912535,9.2075));
#823=CARTESIAN_POINT('',(-2.54,-170.939773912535,9.0805));
#824=CARTESIAN_POINT('',(-2.54,-170.939773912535,9.017));
#825=CARTESIAN_POINT('',(-2.54,-170.939773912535,8.89));
#826=CARTESIAN_POINT('',(-2.54,-170.939773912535,8.8265));
#827=CARTESIAN_POINT('',(-2.54,-170.939773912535,8.6995));
#828=CARTESIAN_POINT('',(-2.54,-170.939773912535,8.636));
#829=CARTESIAN_POINT('',(-2.54,-170.939773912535,8.509));
#830=CARTESIAN_POINT('',(-2.54,-170.939773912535,8.4455));
#831=CARTESIAN_POINT('',(-2.54,-170.939773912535,8.3185));
#832=CARTESIAN_POINT('',(-2.54,-170.939773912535,8.255));
#833=CARTESIAN_POINT('',(-2.54,-170.939773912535,8.128));
#834=CARTESIAN_POINT('',(-2.54,-170.939773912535,8.0645));
#835=CARTESIAN_POINT('',(-2.54,-170.939773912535,7.9375));
#836=CARTESIAN_POINT('',(-2.54,-170.939773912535,7.874));
#837=CARTESIAN_POINT('',(-2.54,-170.939773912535,7.747));
#838=CARTESIAN_POINT('',(-2.54,-170.939773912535,7.6835));
#839=CARTESIAN_POINT('',(-2.54,-170.939773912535,7.5565));
#840=CARTESIAN_POINT('',(-2.54,-170.939773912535,7.493));
#841=CARTESIAN_POINT('',(-2.54,-170.939773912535,7.366));
#842=CARTESIAN_POINT('',(-2.54,-170.939773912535,7.3025));
#843=CARTESIAN_POINT('',(-2.54,-170.939773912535,7.1755));
#844=CARTESIAN_POINT('',(-2.54,-170.939773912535,7.112));
#845=CARTESIAN_POINT('',(-2.54,-170.939773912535,6.985));
#846=CARTESIAN_POINT('',(-2.54,-170.939773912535,6.9215));
#847=CARTESIAN_POINT('',(-2.54,-170.939773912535,6.7945));
#848=CARTESIAN_POINT('',(-2.54,-170.939773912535,6.731));
#849=CARTESIAN_POINT('',(-2.54,-170.939773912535,6.604));
#850=CARTESIAN_POINT('',(-2.54,-170.939773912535,6.5405));
#851=CARTESIAN_POINT('',(-2.54,-170.939773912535,6.4135));
#852=CARTESIAN_POINT('',(-2.54,-170.939773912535,6.35));
#853=CARTESIAN_POINT('',(-2.54,-170.939773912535,6.223));
#854=CARTESIAN_POINT('',(-2.54,-170.939773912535,6.1595));
#855=CARTESIAN_POINT('',(-2.54,-170.939773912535,6.0325));
#856=CARTESIAN_POINT('',(-2.54,-170.939773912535,5.969));
#857=CARTESIAN_POINT('',(-2.54,-170.939773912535,5.842));
#858=CARTESIAN_POINT('',(-2.54,-170.939773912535,5.7785));
#859=CARTESIAN_POINT('',(-2.54,-170.939773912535,5.6515));
#860=CARTESIAN_POINT('',(-2.54,-170.939773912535,5.588));
#861=CARTESIAN_POINT('',(-2.54,-170.939773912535,5.461));
#862=CARTESIAN_POINT('',(-2.54,-170.939773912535,5.3975));
#863=CARTESIAN_POINT('',(-2.54,-170.939773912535,5.2705));
#864=CARTESIAN_POINT('',(-2.54,-170.939773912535,5.207));
#865=CARTESIAN_POINT('',(-2.54,-170.939773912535,5.08));
#866=CARTESIAN_POINT('',(-2.54,-170.939773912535,5.0165));
#867=CARTESIAN_POINT('',(-2.54,-170.939773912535,4.8895));
#868=CARTESIAN_POINT('',(-2.54,-170.939773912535,4.826));
#869=CARTESIAN_POINT('',(-2.54,-170.939773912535,4.699));
#870=CARTESIAN_POINT('',(-2.54,-170.939773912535,4.6355));
#871=CARTESIAN_POINT('',(-2.54,-170.939773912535,4.5085));
#872=CARTESIAN_POINT('',(-2.54,-170.939773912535,4.445));
#873=CARTESIAN_POINT('',(-2.54,-170.939773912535,4.318));
#874=CARTESIAN_POINT('',(-2.54,-170.939773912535,4.2545));
#875=CARTESIAN_POINT('',(-2.54,-170.939773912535,4.1275));
#876=CARTESIAN_POINT('',(-2.54,-170.939773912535,4.064));
#877=CARTESIAN_POINT('',(-2.54,-170.939773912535,3.937));
#878=CARTESIAN_POINT('',(-2.54,-170.939773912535,3.8735));
#879=CARTESIAN_POINT('',(-2.54,-170.939773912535,3.7465));
#880=CARTESIAN_POINT('',(-2.54,-170.939773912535,3.683));
#881=CARTESIAN_POINT('',(-2.54,-170.939773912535,3.556));
#882=CARTESIAN_POINT('',(-2.54,-170.939773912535,3.4925));
#883=CARTESIAN_POINT('',(-2.54,-170.939773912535,3.429));
#884=B_SPLINE_CURVE_WITH_KNOTS('',3,(#818,#819,#820,#821,#822,#823,#824,#825,#826,#827,#828,
#829,#830,#831,#832,#833,#834,#835,#836,#837,#838,#839,#840,#841,#842,#843,#844,#845,#846,#847,
#848,#849,#850,#851,#852,#853,#854,#855,#856,#857,#858,#859,#860,#861,#862,#863,#864,#865,#866,
#867,#868,#869,#870,#871,#872,#873,#874,#875,#876,#877,#878,#879,#880,#881,#882,#883),
.UNSPECIFIED.,.F.,.F.,(4,2,2,2,2,2,2,2,2,2,2,2,2,2,2,2,2,2,2,2,2,2,2,2,2,2,2,2,2,2,2,2,4),(0.,
0.1905,0.380999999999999,0.571499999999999,0.761999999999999,0.952499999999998,1.143,1.3335,
1.524,1.7145,1.905,2.0955,2.286,2.4765,2.667,2.8575,3.048,3.2385,3.429,3.6195,3.81,4.0005,4.191,
4.3815,4.572,4.7625,4.953,5.1435,5.334,5.5245,5.715,5.9055,6.096),.UNSPECIFIED.);
#885=EDGE_CURVE('BSEAM646',#808,#816,#884,.T.);
#886=ORIENTED_EDGE('',*,*,#809,.T.);
#887=ORIENTED_EDGE('',*,*,#817,.T.);
#888=ORIENTED_EDGE('',*,*,#885,.T.);
#889=ORIENTED_EDGE('',*,*,#885,.F.);
#890=EDGE_LOOP('',(#886,#888,#887,#889));
#891=FACE_BOUND('',#890,.T.);
#892=ADVANCED_FACE('F646',(#891),#718,.F.);
#893=CARTESIAN_POINT('',(88.9,-170.939773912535,9.525));
#894=DIRECTION('',(0.,0.,1.));
#895=DIRECTION('',(1.,0.,0.));
#896=AXIS2_PLACEMENT_3D('',#893,#894,#895);
#897=PLANE('',#896);
#898=CARTESIAN_POINT('',(88.9,-170.939773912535,9.525));
#899=DIRECTION('',(0.,0.,1.));
#900=DIRECTION('',(1.,0.,0.));
#901=AXIS2_PLACEMENT_3D('',#898,#899,#900);
#902=CIRCLE('',#901,15.24);
#903=EDGE_CURVE('E374',#587,#691,#902,.T.);
#904=ORIENTED_EDGE('',*,*,#903,.F.);
#905=ORIENTED_EDGE('',*,*,#588,.T.);
#906=ORIENTED_EDGE('',*,*,#653,.T.);
#907=ORIENTED_EDGE('',*,*,#694,.T.);
#908=EDGE_LOOP('',(#904,#905,#906,#907));
#909=FACE_BOUND('',#908,.T.);
#910=ORIENTED_EDGE('',*,*,#809,.F.);
#911=EDGE_LOOP('',(#910));
#912=FACE_BOUND('',#911,.T.);
#913=ADVANCED_FACE('F499',(#909,#912),#897,.T.);
#914=CARTESIAN_POINT('',(88.9,-170.939773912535,9.525));
#915=DIRECTION('',(0.,0.,-1.));
#916=DIRECTION('',(-1.,0.,0.));
#917=AXIS2_PLACEMENT_3D('',#914,#915,#916);
#918=CYLINDRICAL_SURFACE('',#917,15.24);
#919=ORIENTED_EDGE('',*,*,#684,.T.);
#920=EDGE_CURVE('E358',#675,#512,#510,.T.);
#921=ORIENTED_EDGE('',*,*,#920,.T.);
#922=ORIENTED_EDGE('',*,*,#515,.T.);
#923=EDGE_CURVE('E364',#514,#599,#510,.T.);
#924=ORIENTED_EDGE('',*,*,#923,.T.);
#925=ORIENTED_EDGE('',*,*,#600,.F.);
#926=EDGE_CURVE('E419',#591,#587,#902,.T.);
#927=ORIENTED_EDGE('',*,*,#926,.T.);
#928=ORIENTED_EDGE('',*,*,#903,.T.);
#929=EDGE_CURVE('E362',#691,#683,#902,.T.);
#930=ORIENTED_EDGE('',*,*,#929,.T.);
#931=EDGE_LOOP('',(#919,#921,#922,#924,#925,#927,#928,#930));
#932=FACE_BOUND('',#931,.T.);
#933=CARTESIAN_POINT('',(88.9,-170.939773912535,73.025));
#934=DIRECTION('',(0.,0.,1.));
#935=DIRECTION('',(1.,0.,0.));
#936=AXIS2_PLACEMENT_3D('',#933,#934,#935);
#937=CIRCLE('',#936,15.24);
#938=EDGE_CURVE('E426',#421,#361,#937,.T.);
#939=ORIENTED_EDGE('',*,*,#938,.F.);
#940=EDGE_CURVE('E509',#361,#421,#937,.T.);
#941=ORIENTED_EDGE('',*,*,#940,.F.);
#942=EDGE_LOOP('',(#939,#941));
#943=FACE_BOUND('',#942,.T.);
#944=CARTESIAN_POINT('',(88.9,-170.939773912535,-73.025));
#945=DIRECTION('',(0.,0.,-1.));
#946=DIRECTION('',(-1.,0.,0.));
#947=AXIS2_PLACEMENT_3D('',#944,#945,#946);
#948=CIRCLE('',#947,15.24);
#949=EDGE_CURVE('E359',#197,#109,#948,.T.);
#950=ORIENTED_EDGE('',*,*,#949,.F.);
#951=EDGE_CURVE('E363',#109,#197,#948,.T.);
#952=ORIENTED_EDGE('',*,*,#951,.F.);
#953=EDGE_LOOP('',(#950,#952));
#954=FACE_BOUND('',#953,.T.);
#955=ADVANCED_FACE('F34',(#932,#943,#954),#918,.T.);
#956=CARTESIAN_POINT('',(6.35,-158.057189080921,-3.429));
#957=DIRECTION('',(1.,0.,0.));
#958=DIRECTION('',(0.,0.,-1.));
#959=AXIS2_PLACEMENT_3D('',#956,#957,#958);
#960=PLANE('',#959);
#961=DIRECTION('',(0.,1.,0.));
#962=VECTOR('',#961,1.);
#963=CARTESIAN_POINT('',(6.35,-183.457189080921,-3.429));
#964=LINE('',#963,#962);
#965=EDGE_CURVE('E423',#669,#553,#964,.T.);
#966=ORIENTED_EDGE('',*,*,#965,.F.);
#967=ORIENTED_EDGE('',*,*,#709,.F.);
#968=DIRECTION('',(0.,-1.,0.));
#969=VECTOR('',#968,1.);
#970=CARTESIAN_POINT('',(6.35,-158.057189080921,3.429));
#971=LINE('',#970,#969);
#972=EDGE_CURVE('E404',#563,#702,#971,.T.);
#973=ORIENTED_EDGE('',*,*,#972,.F.);
#974=ORIENTED_EDGE('',*,*,#564,.F.);
#975=EDGE_LOOP('',(#966,#967,#973,#974));
#976=FACE_BOUND('',#975,.T.);
#977=ADVANCED_FACE('F632',(#976),#960,.F.);
#978=CARTESIAN_POINT('',(6.35,-183.457189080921,-3.429));
#979=DIRECTION('',(0.,0.,1.));
#980=DIRECTION('',(0.,-1.,0.));
#981=AXIS2_PLACEMENT_3D('',#978,#979,#980);
#982=PLANE('',#981);
#983=ORIENTED_EDGE('',*,*,#726,.F.);
#984=EDGE_LOOP('',(#983));
#985=FACE_BOUND('',#984,.T.);
#986=ORIENTED_EDGE('',*,*,#556,.T.);
#987=ORIENTED_EDGE('',*,*,#622,.T.);
#988=ORIENTED_EDGE('',*,*,#670,.T.);
#989=ORIENTED_EDGE('',*,*,#965,.T.);
#990=EDGE_LOOP('',(#986,#987,#988,#989));
#991=FACE_BOUND('',#990,.T.);
#992=ADVANCED_FACE('F635',(#985,#991),#982,.T.);
#993=CARTESIAN_POINT('',(6.35,-158.057189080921,3.429));
#994=DIRECTION('',(0.,0.,-1.));
#995=DIRECTION('',(0.,1.,0.));
#996=AXIS2_PLACEMENT_3D('',#993,#994,#995);
#997=PLANE('',#996);
#998=ORIENTED_EDGE('',*,*,#817,.F.);
#999=EDGE_LOOP('',(#998));
#1000=FACE_BOUND('',#999,.T.);
#1001=ORIENTED_EDGE('',*,*,#572,.T.);
#1002=ORIENTED_EDGE('',*,*,#972,.T.);
#1003=ORIENTED_EDGE('',*,*,#703,.T.);
#1004=ORIENTED_EDGE('',*,*,#642,.T.);
#1005=EDGE_LOOP('',(#1001,#1002,#1003,#1004));
#1006=FACE_BOUND('',#1005,.T.);
#1007=ADVANCED_FACE('F631',(#1000,#1006),#997,.T.);
#1008=CARTESIAN_POINT('',(88.9,-170.939773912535,9.525));
#1009=DIRECTION('',(0.,0.,1.));
#1010=DIRECTION('',(1.,0.,0.));
#1011=AXIS2_PLACEMENT_3D('',#1008,#1009,#1010);
#1012=PLANE('',#1011);
#1013=ORIENTED_EDGE('',*,*,#926,.F.);
#1014=ORIENTED_EDGE('',*,*,#592,.T.);
#1015=EDGE_LOOP('',(#1013,#1014));
#1016=FACE_BOUND('',#1015,.T.);
#1017=ADVANCED_FACE('F508',(#1016),#1012,.F.);
#1018=ORIENTED_EDGE('',*,*,#929,.F.);
#1019=ORIENTED_EDGE('',*,*,#692,.T.);
#1020=EDGE_LOOP('',(#1018,#1019));
#1021=FACE_BOUND('',#1020,.T.);
#1022=ADVANCED_FACE('F494',(#1021),#1012,.F.);
#1023=CARTESIAN_POINT('',(88.9,-170.939773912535,73.025));
#1024=DIRECTION('',(0.,0.,1.));
#1025=DIRECTION('',(1.,0.,0.));
#1026=AXIS2_PLACEMENT_3D('',#1023,#1024,#1025);
#1027=PLANE('',#1026);
#1028=ORIENTED_EDGE('',*,*,#422,.F.);
#1029=CARTESIAN_POINT('',(88.9,-170.939773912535,73.025));
#1030=DIRECTION('',(0.,0.,1.));
#1031=DIRECTION('',(1.,0.,0.));
#1032=AXIS2_PLACEMENT_3D('',#1029,#1030,#1031);
#1033=CIRCLE('',#1032,15.2397728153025);
#1034=EDGE_CURVE('E338',#365,#413,#1033,.T.);
#1035=ORIENTED_EDGE('',*,*,#1034,.F.);
#1036=ORIENTED_EDGE('',*,*,#366,.F.);
#1037=ORIENTED_EDGE('',*,*,#940,.T.);
#1038=EDGE_LOOP('',(#1028,#1035,#1036,#1037));
#1039=FACE_BOUND('',#1038,.T.);
#1040=ADVANCED_FACE('F538',(#1039),#1027,.T.);
#1041=CARTESIAN_POINT('',(88.9,-170.939773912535,-9.525));
#1042=DIRECTION('',(0.,0.,-1.));
#1043=DIRECTION('',(-1.,0.,0.));
#1044=AXIS2_PLACEMENT_3D('',#1041,#1042,#1043);
#1045=PLANE('',#1044);
#1046=ORIENTED_EDGE('',*,*,#676,.F.);
#1047=ORIENTED_EDGE('',*,*,#920,.F.);
#1048=EDGE_LOOP('',(#1046,#1047));
#1049=FACE_BOUND('',#1048,.T.);
#1050=ADVANCED_FACE('F487',(#1049),#1045,.F.);
#1051=CARTESIAN_POINT('',(88.9,-170.939773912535,-73.025));
#1052=DIRECTION('',(0.,0.,-1.));
#1053=DIRECTION('',(-1.,0.,0.));
#1054=AXIS2_PLACEMENT_3D('',#1051,#1052,#1053);
#1055=PLANE('',#1054);
#1056=ORIENTED_EDGE('',*,*,#198,.F.);
#1057=CARTESIAN_POINT('',(88.9,-170.939773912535,-73.025));
#1058=DIRECTION('',(0.,0.,-1.));
#1059=DIRECTION('',(-1.,0.,0.));
#1060=AXIS2_PLACEMENT_3D('',#1057,#1058,#1059);
#1061=CIRCLE('',#1060,15.2397728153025);
#1062=EDGE_CURVE('E303',#113,#189,#1061,.T.);
#1063=ORIENTED_EDGE('',*,*,#1062,.F.);
#1064=ORIENTED_EDGE('',*,*,#114,.F.);
#1065=ORIENTED_EDGE('',*,*,#951,.T.);
#1066=EDGE_LOOP('',(#1056,#1063,#1064,#1065));
#1067=FACE_BOUND('',#1066,.T.);
#1068=ADVANCED_FACE('F583',(#1067),#1055,.T.);
#1069=ORIENTED_EDGE('',*,*,#602,.F.);
#1070=ORIENTED_EDGE('',*,*,#923,.F.);
#1071=EDGE_LOOP('',(#1069,#1070));
#1072=FACE_BOUND('',#1071,.T.);
#1073=ADVANCED_FACE('F610',(#1072),#1045,.F.);
#1074=CARTESIAN_POINT('',(88.9,-82.0397739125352,73.025));
#1075=DIRECTION('',(0.,0.,1.));
#1076=DIRECTION('',(1.,0.,0.));
#1077=AXIS2_PLACEMENT_3D('',#1074,#1075,#1076);
#1078=PLANE('',#1077);
#1079=ORIENTED_EDGE('',*,*,#474,.T.);
#1080=EDGE_LOOP('',(#1079));
#1081=FACE_BOUND('',#1080,.T.);
#1082=ORIENTED_EDGE('',*,*,#424,.F.);
#1083=ORIENTED_EDGE('',*,*,#938,.T.);
#1084=ORIENTED_EDGE('',*,*,#362,.F.);
#1085=ORIENTED_EDGE('',*,*,#321,.F.);
#1086=EDGE_LOOP('',(#1082,#1083,#1084,#1085));
#1087=FACE_BOUND('',#1086,.T.);
#1088=ADVANCED_FACE('F517',(#1081,#1087),#1078,.F.);
#1089=CARTESIAN_POINT('',(88.9,-170.939773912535,92.075));
#1090=DIRECTION('',(0.,0.,-1.));
#1091=DIRECTION('',(-1.,0.,0.));
#1092=AXIS2_PLACEMENT_3D('',#1089,#1090,#1091);
#1093=CYLINDRICAL_SURFACE('',#1092,15.2397728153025);
#1094=ORIENTED_EDGE('',*,*,#1034,.T.);
#1095=ORIENTED_EDGE('',*,*,#414,.F.);
#1096=CARTESIAN_POINT('',(88.9,-170.939773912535,92.075));
#1097=DIRECTION('',(0.,0.,1.));
#1098=DIRECTION('',(1.,0.,0.));
#1099=AXIS2_PLACEMENT_3D('',#1096,#1097,#1098);
#1100=CIRCLE('',#1099,15.2397728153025);
#1101=EDGE_CURVE('E328',#373,#405,#1100,.T.);
#1102=ORIENTED_EDGE('',*,*,#1101,.F.);
#1103=ORIENTED_EDGE('',*,*,#374,.T.);
#1104=EDGE_LOOP('',(#1094,#1095,#1102,#1103));
#1105=FACE_BOUND('',#1104,.T.);
#1106=ADVANCED_FACE('F540',(#1105),#1093,.T.);
#1107=CARTESIAN_POINT('',(88.9,-82.0397739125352,92.075));
#1108=DIRECTION('',(0.,0.,1.));
#1109=DIRECTION('',(1.,0.,0.));
#1110=AXIS2_PLACEMENT_3D('',#1107,#1108,#1109);
#1111=PLANE('',#1110);
#1112=CARTESIAN_POINT('',(88.9,-170.939773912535,92.075));
#1113=DIRECTION('',(0.,0.,-1.));
#1114=DIRECTION('',(-1.,0.,0.));
#1115=AXIS2_PLACEMENT_3D('',#1112,#1113,#1114);
#1116=CIRCLE('',#1115,5.08);
#1117=CARTESIAN_POINT('',(83.82,-170.939773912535,92.075));
#1118=VERTEX_POINT('',#1117);
#1119=EDGE_CURVE('E269',#1118,#1118,#1116,.T.);
#1120=ORIENTED_EDGE('',*,*,#1119,.T.);
#1121=EDGE_LOOP('',(#1120));
#1122=FACE_BOUND('',#1121,.T.);
#1123=ORIENTED_EDGE('',*,*,#451,.T.);
#1124=EDGE_LOOP('',(#1123));
#1125=FACE_BOUND('',#1124,.T.);
#1126=ORIENTED_EDGE('',*,*,#288,.T.);
#1127=ORIENTED_EDGE('',*,*,#380,.T.);
#1128=ORIENTED_EDGE('',*,*,#1101,.T.);
#1129=ORIENTED_EDGE('',*,*,#406,.T.);
#1130=EDGE_LOOP('',(#1126,#1127,#1128,#1129));
#1131=FACE_BOUND('',#1130,.T.);
#1132=ADVANCED_FACE('F545',(#1122,#1125,#1131),#1111,.T.);
#1133=CARTESIAN_POINT('',(88.9,-82.0397739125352,-73.025));
#1134=DIRECTION('',(0.,0.,-1.));
#1135=DIRECTION('',(-1.,0.,0.));
#1136=AXIS2_PLACEMENT_3D('',#1133,#1134,#1135);
#1137=PLANE('',#1136);
#1138=ORIENTED_EDGE('',*,*,#218,.T.);
#1139=EDGE_LOOP('',(#1138));
#1140=FACE_BOUND('',#1139,.T.);
#1141=ORIENTED_EDGE('',*,*,#200,.F.);
#1142=ORIENTED_EDGE('',*,*,#949,.T.);
#1143=ORIENTED_EDGE('',*,*,#110,.F.);
#1144=ORIENTED_EDGE('',*,*,#50,.F.);
#1145=EDGE_LOOP('',(#1141,#1142,#1143,#1144));
#1146=FACE_BOUND('',#1145,.T.);
#1147=ADVANCED_FACE('F578',(#1140,#1146),#1137,.F.);
#1148=CARTESIAN_POINT('',(88.9,-170.939773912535,-92.075));
#1149=DIRECTION('',(0.,0.,1.));
#1150=DIRECTION('',(1.,0.,0.));
#1151=AXIS2_PLACEMENT_3D('',#1148,#1149,#1150);
#1152=CYLINDRICAL_SURFACE('',#1151,15.2397728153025);
#1153=ORIENTED_EDGE('',*,*,#1062,.T.);
#1154=ORIENTED_EDGE('',*,*,#190,.F.);
#1155=CARTESIAN_POINT('',(88.9,-170.939773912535,-92.075));
#1156=DIRECTION('',(0.,0.,-1.));
#1157=DIRECTION('',(-1.,0.,0.));
#1158=AXIS2_PLACEMENT_3D('',#1155,#1156,#1157);
#1159=CIRCLE('',#1158,15.2397728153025);
#1160=EDGE_CURVE('E293',#121,#181,#1159,.T.);
#1161=ORIENTED_EDGE('',*,*,#1160,.F.);
#1162=ORIENTED_EDGE('',*,*,#122,.T.);
#1163=EDGE_LOOP('',(#1153,#1154,#1161,#1162));
#1164=FACE_BOUND('',#1163,.T.);
#1165=ADVANCED_FACE('F587',(#1164),#1152,.T.);
#1166=CARTESIAN_POINT('',(88.9,-82.0397739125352,-92.075));
#1167=DIRECTION('',(0.,0.,-1.));
#1168=DIRECTION('',(-1.,0.,0.));
#1169=AXIS2_PLACEMENT_3D('',#1166,#1167,#1168);
#1170=PLANE('',#1169);
#1171=CARTESIAN_POINT('',(88.9,-170.939773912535,-92.075));
#1172=DIRECTION('',(0.,0.,-1.));
#1173=DIRECTION('',(-1.,0.,0.));
#1174=AXIS2_PLACEMENT_3D('',#1171,#1172,#1173);
#1175=CIRCLE('',#1174,5.08);
#1176=CARTESIAN_POINT('',(83.82,-170.939773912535,-92.075));
#1177=VERTEX_POINT('',#1176);
#1178=EDGE_CURVE('E268',#1177,#1177,#1175,.T.);
#1179=ORIENTED_EDGE('',*,*,#1178,.F.);
#1180=EDGE_LOOP('',(#1179));
#1181=FACE_BOUND('',#1180,.T.);
#1182=ORIENTED_EDGE('',*,*,#241,.F.);
#1183=EDGE_LOOP('',(#1182));
#1184=FACE_BOUND('',#1183,.T.);
#1185=ORIENTED_EDGE('',*,*,#83,.T.);
#1186=ORIENTED_EDGE('',*,*,#128,.T.);
#1187=ORIENTED_EDGE('',*,*,#1160,.T.);
#1188=ORIENTED_EDGE('',*,*,#182,.T.);
#1189=EDGE_LOOP('',(#1185,#1186,#1187,#1188));
#1190=FACE_BOUND('',#1189,.T.);
#1191=ADVANCED_FACE('F591',(#1181,#1184,#1190),#1170,.T.);
#1192=CARTESIAN_POINT('',(88.9,-170.939773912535,92.075));
#1193=DIRECTION('',(0.,0.,-1.));
#1194=DIRECTION('',(-1.,0.,0.));
#1195=AXIS2_PLACEMENT_3D('',#1192,#1193,#1194);
#1196=CYLINDRICAL_SURFACE('',#1195,5.08);
#1197=ORIENTED_EDGE('',*,*,#1119,.F.);
#1198=EDGE_LOOP('',(#1197));
#1199=FACE_BOUND('',#1198,.T.);
#1200=ORIENTED_EDGE('',*,*,#1178,.T.);
#1201=EDGE_LOOP('',(#1200));
#1202=FACE_BOUND('',#1201,.T.);
#1203=ADVANCED_FACE('F765',(#1199,#1202),#1196,.F.);
#1204=CARTESIAN_POINT('',(104.14,-91.3760339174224,85.979));
#1205=DIRECTION('',(0.,1.,0.));
#1206=DIRECTION('',(0.,0.,1.));
#1207=AXIS2_PLACEMENT_3D('',#1204,#1205,#1206);
#1208=PLANE('',#1207);
#1209=ORIENTED_EDGE('',*,*,#347,.T.);
#1210=DIRECTION('',(-1.,0.,0.));
#1211=VECTOR('',#1210,1.);
#1212=CARTESIAN_POINT('',(104.14,-91.3760339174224,85.979));
#1213=LINE('',#1212,#1211);
#1214=EDGE_CURVE('E249',#396,#338,#1213,.T.);
#1215=ORIENTED_EDGE('',*,*,#1214,.F.);
#1216=ORIENTED_EDGE('',*,*,#439,.T.);
#1217=DIRECTION('',(-1.,0.,0.));
#1218=VECTOR('',#1217,1.);
#1219=CARTESIAN_POINT('',(104.14,-91.3760339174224,79.121));
#1220=LINE('',#1219,#1218);
#1221=EDGE_CURVE('E55',#432,#346,#1220,.T.);
#1222=ORIENTED_EDGE('',*,*,#1221,.T.);
#1223=EDGE_LOOP('',(#1209,#1215,#1216,#1222));
#1224=FACE_BOUND('',#1223,.T.);
#1225=ADVANCED_FACE('F773',(#1224),#1208,.T.);
#1226=CARTESIAN_POINT('',(104.14,-65.9760339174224,85.979));
#1227=DIRECTION('',(0.,0.,-1.));
#1228=DIRECTION('',(0.,1.,0.));
#1229=AXIS2_PLACEMENT_3D('',#1226,#1227,#1228);
#1230=PLANE('',#1229);
#1231=ORIENTED_EDGE('',*,*,#462,.T.);
#1232=EDGE_LOOP('',(#1231));
#1233=FACE_BOUND('',#1232,.T.);
#1234=ORIENTED_EDGE('',*,*,#339,.T.);
#1235=ORIENTED_EDGE('',*,*,#271,.T.);
#1236=ORIENTED_EDGE('',*,*,#397,.T.);
#1237=ORIENTED_EDGE('',*,*,#1214,.T.);
#1238=EDGE_LOOP('',(#1234,#1235,#1236,#1237));
#1239=FACE_BOUND('',#1238,.T.);
#1240=ADVANCED_FACE('F551',(#1233,#1239),#1230,.T.);
#1241=CARTESIAN_POINT('',(104.14,-65.9760339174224,79.121));
#1242=DIRECTION('',(0.,0.,1.));
#1243=DIRECTION('',(0.,-1.,0.));
#1244=AXIS2_PLACEMENT_3D('',#1241,#1242,#1243);
#1245=PLANE('',#1244);
#1246=ORIENTED_EDGE('',*,*,#485,.T.);
#1247=EDGE_LOOP('',(#1246));
#1248=FACE_BOUND('',#1247,.T.);
#1249=ORIENTED_EDGE('',*,*,#353,.T.);
#1250=ORIENTED_EDGE('',*,*,#1221,.F.);
#1251=ORIENTED_EDGE('',*,*,#433,.T.);
#1252=ORIENTED_EDGE('',*,*,#308,.T.);
#1253=EDGE_LOOP('',(#1249,#1250,#1251,#1252));
#1254=FACE_BOUND('',#1253,.T.);
#1255=ADVANCED_FACE('F789',(#1248,#1254),#1245,.T.);
#1256=CARTESIAN_POINT('',(104.14,-93.106885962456,-79.121));
#1257=DIRECTION('',(0.,1.,0.));
#1258=DIRECTION('',(0.,0.,1.));
#1259=AXIS2_PLACEMENT_3D('',#1256,#1257,#1258);
#1260=PLANE('',#1259);
#1261=ORIENTED_EDGE('',*,*,#143,.T.);
#1262=DIRECTION('',(-1.,0.,0.));
#1263=VECTOR('',#1262,1.);
#1264=CARTESIAN_POINT('',(104.14,-93.106885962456,-85.979));
#1265=LINE('',#1264,#1263);
#1266=EDGE_CURVE('E220',#136,#166,#1265,.T.);
#1267=ORIENTED_EDGE('',*,*,#1266,.T.);
#1268=ORIENTED_EDGE('',*,*,#167,.T.);
#1269=DIRECTION('',(-1.,0.,0.));
#1270=VECTOR('',#1269,1.);
#1271=CARTESIAN_POINT('',(104.14,-93.106885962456,-79.121));
#1272=LINE('',#1271,#1270);
#1273=EDGE_CURVE('E223',#100,#158,#1272,.T.);
#1274=ORIENTED_EDGE('',*,*,#1273,.F.);
#1275=EDGE_LOOP('',(#1261,#1267,#1268,#1274));
#1276=FACE_BOUND('',#1275,.T.);
#1277=ADVANCED_FACE('F219',(#1276),#1260,.T.);
#1278=CARTESIAN_POINT('',(104.14,-67.706885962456,-79.121));
#1279=DIRECTION('',(0.,0.,-1.));
#1280=DIRECTION('',(0.,1.,0.));
#1281=AXIS2_PLACEMENT_3D('',#1278,#1279,#1280);
#1282=PLANE('',#1281);
#1283=ORIENTED_EDGE('',*,*,#229,.T.);
#1284=EDGE_LOOP('',(#1283));
#1285=FACE_BOUND('',#1284,.T.);
#1286=ORIENTED_EDGE('',*,*,#101,.T.);
#1287=ORIENTED_EDGE('',*,*,#1273,.T.);
#1288=ORIENTED_EDGE('',*,*,#159,.T.);
#1289=ORIENTED_EDGE('',*,*,#33,.T.);
#1290=EDGE_LOOP('',(#1286,#1287,#1288,#1289));
#1291=FACE_BOUND('',#1290,.T.);
#1292=ADVANCED_FACE('F566',(#1285,#1291),#1282,.T.);
#1293=CARTESIAN_POINT('',(104.14,-67.706885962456,-85.979));
#1294=DIRECTION('',(0.,0.,1.));
#1295=DIRECTION('',(0.,-1.,0.));
#1296=AXIS2_PLACEMENT_3D('',#1293,#1294,#1295);
#1297=PLANE('',#1296);
#1298=ORIENTED_EDGE('',*,*,#252,.T.);
#1299=EDGE_LOOP('',(#1298));
#1300=FACE_BOUND('',#1299,.T.);
#1301=ORIENTED_EDGE('',*,*,#137,.T.);
#1302=ORIENTED_EDGE('',*,*,#70,.T.);
#1303=ORIENTED_EDGE('',*,*,#173,.T.);
#1304=ORIENTED_EDGE('',*,*,#1266,.F.);
#1305=EDGE_LOOP('',(#1301,#1302,#1303,#1304));
#1306=FACE_BOUND('',#1305,.T.);
#1307=ADVANCED_FACE('F229',(#1300,#1306),#1297,.T.);
#1308=CLOSED_SHELL('',(#60,#89,#147,#205,#233,#256,#298,#327,#385,#443,#466,#489,#542,#609,#634,
#658,#713,#801,#892,#913,#955,#977,#992,#1007,#1017,#1022,#1040,#1050,#1068,#1073,#1088,#1106,
#1132,#1147,#1165,#1191,#1203,#1225,#1240,#1255,#1277,#1292,#1307));
#1309=MANIFOLD_SOLID_BREP('B2',#1308);
#1310=ADVANCED_BREP_SHAPE_REPRESENTATION('',(#18,#1309),#14);
#1311=SHAPE_DEFINITION_REPRESENTATION(#9,#1310);
ENDSEC;
END-ISO-10303-21;
